! (c) 2009  Infineon Technologies AG, Munich
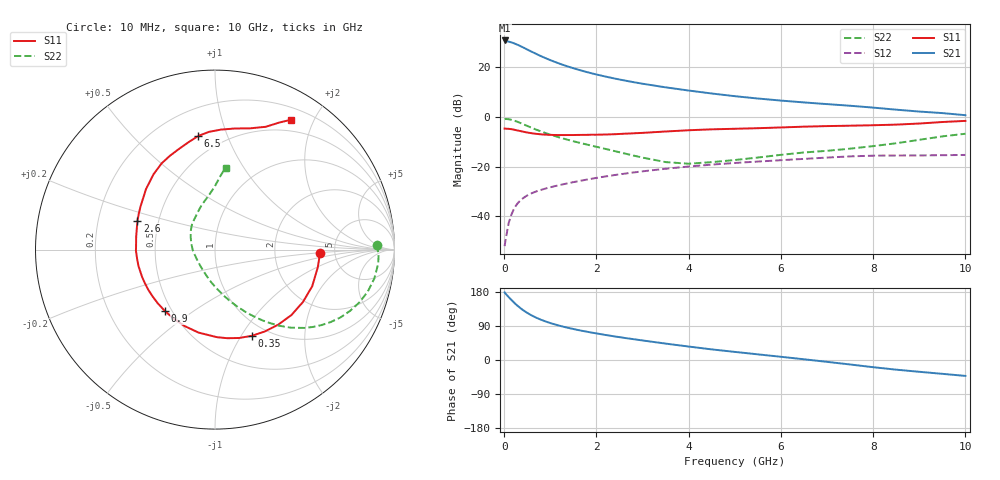
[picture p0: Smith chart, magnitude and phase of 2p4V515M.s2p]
! Infineon Technologies  Discrete & RF Semiconductors
! BFP420
! VCE =  4.5 V,  IC =  15 mA
! Common Emitter S-Parameters:  Nov 2009
# GHz  S  MA  R  50
!  f  S11  S21  S12  S22
! GHz  MAG  ANG  MAG  ANG  MAG  ANG  MAG  ANG
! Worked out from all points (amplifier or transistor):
!   46 points, 10 MHz to 10 GHz, reference 50 ohm
!   highest |S21| = 30.9 dB at 10 MHz (marker M1)
!   |S21| within 3 dB of that: start of sweep to 433 MHz
!   unconditionally stable (mu >= 1): start of sweep to 23.72 MHz; 2.039 GHz to end of sweep
!   at 300 MHz: K = 0.37, MSG = 31.8 dB, |S12| = -34.6 dB
!   at 1.7 GHz: K = 0.92, MSG = 22.1 dB, |S12| = -25.5 dB
!   at 10 GHz: K = 1.08, MAG = 6.3 dB, |S12| = -15.3 dB
!   lowest NFmin = 1.06 dB at 900 MHz
!   S11 on the Smith chart (normalised r, x): 10 MHz: 3.81, -0.24; 350 MHz: 0.84, -1.11; 900 MHz: 0.46, -0.39; 2.6 GHz: 0.38, +0.16; 6.5 GHz: 0.37, +0.79; 10 GHz: 0.35, +1.68
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0.01  0.5855 -2.0  34.93 178.4  0.0025 19.6  0.9017 1.6
0.02  0.5835 -3.9  33.91 176.5  0.0029 33.3  0.9117 -1.6
0.1  0.5788 -20.7  33.02 165.8  0.0074 62.1  0.9022 -10.3
0.15  0.5704 -30.8  32.08 159.4  0.0104 65.0  0.8825 -15.4
0.2  0.5605 -40.6  30.98 153.3  0.0133 64.3  0.8564 -20.1
0.25  0.5467 -49.9  29.62 147.4  0.0161 62.8  0.8265 -24.4
0.3  0.5338 -58.8  28.36 142.1  0.0186 61.2  0.7938 -28.5
0.35  0.5221 -67.0  26.98 137.2  0.0208 59.5  0.7602 -32.1
0.45  0.4986 -82.0  24.29 128.3  0.0246 56.5  0.6942 -38.4
0.6  0.4716 -101.1  20.67 117.3  0.0292 53.2  0.6057 -45.9
0.7  0.4583 -111.8  18.63 111.4  0.0318 51.8  0.5556 -49.8
0.9  0.4417 -129.1  15.35 101.6  0.0363 50.2  0.4753 -56.1
1.2  0.4339 -149.0  11.91 90.5  0.0425 49.0  0.3873 -63.8
1.7  0.4366 -172.0  8.514 76.8  0.0529 47.7  0.2925 -74.5
2.2  0.4448 170.9  6.528 66.0  0.0636 45.6  0.2275 -85.2
2.6  0.461 159.5  5.475 58.4  0.0721 43.4  0.1856 -95.8
3.5  0.5114 138.7  3.969 43.3  0.0907 37.1  0.1237 -130.2
5.5  0.5959 109.6  2.362 14.9  0.1268 20.8  0.1528 152.5
6.5  0.6398 98.4  1.97 1.9  0.1435 12.5  0.1931 131.3
7  0.657 92.9  1.822 -4.9  0.1525 8.0  0.2087 122.2
8.5  0.7036 73.8  1.408 -25.5  0.1678 -8.4  0.2963 97.9
10  0.8363 59.8  1.089 -42.0  0.1724 -19.3  0.4607 82.7
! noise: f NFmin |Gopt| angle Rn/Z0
0.9  1.06  0.09  -152  0.13
1.8  1.36  0.18  -147  0.12
2.4  1.49  0.17  -148  0.14
3  1.53  0.25  -138  0.14
4  1.67  0.38  -119  0.2
5  2.14  0.44  -103  0.32
6  2.48  0.5  -88  0.47
